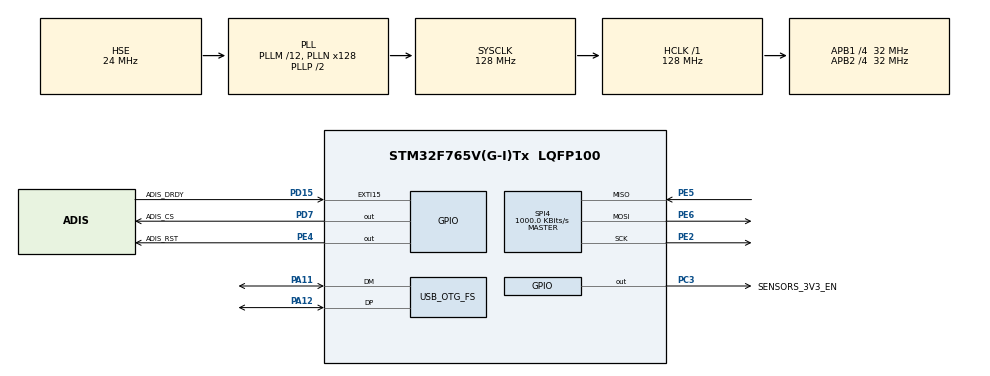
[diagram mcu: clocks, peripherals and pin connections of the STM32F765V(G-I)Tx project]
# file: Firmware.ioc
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Mcu.Family=STM32F7
Mcu.Name=STM32F765V(G-I)Tx
Mcu.Package=LQFP100
NVIC.EXTI15_10_IRQn=true\:0\:0\:false\:false\:true\:true\:true
NVIC.OTG_FS_IRQn=true\:0\:0\:false\:false\:true\:false\:true
NVIC.PriorityGroup=NVIC_PRIORITYGROUP_4
NVIC.TIM1_UP_TIM10_IRQn=true\:0\:0\:false\:false\:true\:true\:true
PA11.Mode=Device_Only
PA11.Signal=USB_OTG_FS_DM
PA12.Mode=Device_Only
PA12.Signal=USB_OTG_FS_DP
PA13.Mode=Serial_Wire
PA13.Signal=SYS_JTMS-SWDIO
PA14.Mode=Serial_Wire
PA14.Signal=SYS_JTCK-SWCLK
PC3.GPIO_Label=SENSORS_3V3_EN
PC3.PinState=GPIO_PIN_SET
PC3.Signal=GPIO_Output
PD15.GPIO_Label=ADIS_DRDY
PD15.Signal=GPXTI15
PD7.GPIO_Label=ADIS_CS
PD7.PinState=GPIO_PIN_SET
PD7.Signal=GPIO_Output
PE2.Mode=Full_Duplex_Master
PE2.Signal=SPI4_SCK
PE4.GPIO_Label=ADIS_RST
PE4.GPIO_ModeDefaultOutputPP=GPIO_MODE_OUTPUT_OD
PE4.GPIO_PuPd=GPIO_PULLUP
PE4.PinState=GPIO_PIN_SET
PE4.Signal=GPIO_Output
PE5.Mode=Full_Duplex_Master
PE5.Signal=SPI4_MISO
PE6.Mode=Full_Duplex_Master
PE6.Signal=SPI4_MOSI
PH0/OSC_IN.Mode=HSE-External-Oscillator
PH0/OSC_IN.Signal=RCC_OSC_IN
PH1/OSC_OUT.Mode=HSE-External-Oscillator
PH1/OSC_OUT.Signal=RCC_OSC_OUT
ProjectManager.HeapSize=0x1000
ProjectManager.StackSize=0x1000
ProjectManager.TargetToolchain=MDK-ARM V5
RCC.AHBFreq_Value=128000000
RCC.APB1CLKDivider=RCC_HCLK_DIV4
RCC.APB1Freq_Value=32000000
RCC.APB1TimFreq_Value=64000000
RCC.APB2CLKDivider=RCC_HCLK_DIV4
RCC.APB2Freq_Value=32000000
RCC.APB2TimFreq_Value=64000000
RCC.CortexFreq_Value=128000000
RCC.HCLKFreq_Value=128000000
RCC.HSE_VALUE=24000000
RCC.HSI_VALUE=16000000
RCC.LSE_VALUE=32768
RCC.PLL48CLockSelection=RCC_CLK48SOURCE_PLLSAIP
RCC.PLLM=12
RCC.PLLN=128
RCC.PLLQ=5
RCC.PLLSAIN=96
RCC.PLLSAIP=RCC_PLLSAIP_DIV4
RCC.SYSCLKFreq_VALUE=128000000
RCC.SYSCLKSource=RCC_SYSCLKSOURCE_PLLCLK
RCC.USBFreq_Value=48000000
RCC.VCOOutputFreq_Value=256000000
SPI4.BaudRatePrescaler=SPI_BAUDRATEPRESCALER_32
SPI4.CLKPhase=SPI_PHASE_2EDGE
SPI4.CLKPolarity=SPI_POLARITY_HIGH
SPI4.CalculateBaudRate=1000.0 KBits/s
SPI4.DataSize=SPI_DATASIZE_16BIT
SPI4.Direction=SPI_DIRECTION_2LINES
SPI4.Mode=SPI_MODE_MASTER
SPI4.VirtualType=VM_MASTER
TIM1.Period=10-1
TIM1.Prescaler=64-1
USB_DEVICE.APP_RX_DATA_SIZE-CDC_FS=32
USB_DEVICE.APP_TX_DATA_SIZE-CDC_FS=32
USB_DEVICE.CLASS_NAME_FS=CDC
USB_DEVICE.MANUFACTURER_STRING-CDC_FS=wangfugui
USB_DEVICE.PID_CDC_FS=2333
USB_DEVICE.PRODUCT_STRING_CDC_FS=adis16448bridge
USB_DEVICE.VID-CDC_FS=2333
USB_DEVICE.VirtualMode-CDC_FS=Cdc
USB_DEVICE.VirtualModeFS=Cdc_FS
USB_OTG_FS.Sof_enable=DISABLE
USB_OTG_FS.VirtualMode=Device_Only
VP_TIM1_VS_ClockSourceINT.Mode=Internal
VP_USB_DEVICE_VS_USB_DEVICE_CDC_FS.Mode=CDC_FS
board=custom

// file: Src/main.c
/* USER CODE BEGIN Header */
/**
  ******************************************************************************
  * @file           : main.c
  * @brief          : Main program body
  ******************************************************************************
  * @attention
  *
  * <h2><center>&copy; Copyright (c) 2020 STMicroelectronics.
  * All rights reserved.</center></h2>
  *
  * This software component is licensed by ST under Ultimate Liberty license
  * SLA0044, the "License"; You may not use this file except in compliance with
  * the License. You may obtain a copy of the License at:
  *                             www.st.com/SLA0044
  *
  ******************************************************************************
  */
/* USER CODE END Header */

#include "main.h"
#include "usb_device.h"

/* USER CODE BEGIN Includes */
//#include "usbd_customhid.h"
//#include "usbd_hid.h"
#include "usbd_cdc_if.h"
/* USER CODE END Includes */

SPI_HandleTypeDef hspi4;

TIM_HandleTypeDef htim1;

/* USER CODE BEGIN PV */
extern USBD_HandleTypeDef hUsbDeviceFS;
/* USER CODE END PV */

void SystemClock_Config(void);
static void MX_GPIO_Init(void);
static void MX_SPI4_Init(void);
static void MX_TIM1_Init(void);

int main(void)
{
  /* USER CODE BEGIN 1 */
//// HID Mouse
//  struct mouseHID_t {
//      uint8_t buttons;
//      int8_t x;
//      int8_t y;
//      int8_t wheel;
//  };
//  struct mouseHID_t mouseHID;
//  mouseHID.buttons = 0;
//  mouseHID.x = 10;
//  mouseHID.y = 0;
//  mouseHID.wheel = 0;
  /* USER CODE END 1 */

  /* MCU Configuration--------------------------------------------------------*/

  /* Reset of all peripherals, Initializes the Flash interface and the Systick. */
  HAL_Init();

  /* Configure the system clock */
  SystemClock_Config();

  /* Initialize all configured peripherals */
  MX_GPIO_Init();
  MX_SPI4_Init();
  MX_USB_DEVICE_Init();
  MX_TIM1_Init();
  /* USER CODE BEGIN 2 */
  unsigned char buf[32];
  /* USER CODE END 2 */

  /* Infinite loop */
  while (1)
  {

    /* USER CODE BEGIN 3 */
    #define ADIS_LEN 14
    int16_t spi_addrs[ADIS_LEN]={0x3e00}, spi_buf[ADIS_LEN];

    HAL_GPIO_WritePin(ADIS_CS_GPIO_Port, ADIS_CS_Pin, 0);
    HAL_SPI_TransmitReceive(&hspi4,(uint8_t*)spi_addrs,(uint8_t*)spi_buf,ADIS_LEN+2,1000);
    HAL_GPIO_WritePin(ADIS_CS_GPIO_Port, ADIS_CS_Pin, 1);

    float gx = spi_buf[2]/25.f;
    float gy = spi_buf[3]/25.f;
    float gz = spi_buf[4]/25.f;

    float ax = spi_buf[5]/1200.f*9.8f;
    float ay = spi_buf[6]/1200.f*9.8f;
    float az = spi_buf[7]/1200.f*9.8f;

    char cdc_buf[200];
    sprintf(cdc_buf,"G: %+7.2f %+7.2f %+7.2f  A: %+6.2f %+6.2f %+6.2f\r\n",gx,gy,gz,ax,ay,az);
    CDC_Transmit_FS((uint8_t*)cdc_buf, strlen(cdc_buf));

    HAL_Delay(100);

  }
  /* USER CODE END 3 */
}

void SystemClock_Config(void)
{
  RCC_OscInitTypeDef RCC_OscInitStruct = {0};
  RCC_ClkInitTypeDef RCC_ClkInitStruct = {0};
  RCC_PeriphCLKInitTypeDef PeriphClkInitStruct = {0};

  /** Configure the main internal regulator output voltage
  */
  __HAL_RCC_PWR_CLK_ENABLE();
  __HAL_PWR_VOLTAGESCALING_CONFIG(PWR_REGULATOR_VOLTAGE_SCALE3);
  /** Initializes the CPU, AHB and APB busses clocks
  */
  RCC_OscInitStruct.OscillatorType = RCC_OSCILLATORTYPE_HSE;
  RCC_OscInitStruct.HSEState = RCC_HSE_ON;
  RCC_OscInitStruct.PLL.PLLState = RCC_PLL_ON;
  RCC_OscInitStruct.PLL.PLLSource = RCC_PLLSOURCE_HSE;
  RCC_OscInitStruct.PLL.PLLM = 12;
  RCC_OscInitStruct.PLL.PLLN = 128;
  RCC_OscInitStruct.PLL.PLLP = RCC_PLLP_DIV2;
  RCC_OscInitStruct.PLL.PLLQ = 5;
  if (HAL_RCC_OscConfig(&RCC_OscInitStruct) != HAL_OK)
  {
    Error_Handler();
  }
  /** Initializes the CPU, AHB and APB busses clocks
  */
  RCC_ClkInitStruct.ClockType = RCC_CLOCKTYPE_HCLK|RCC_CLOCKTYPE_SYSCLK
                              |RCC_CLOCKTYPE_PCLK1|RCC_CLOCKTYPE_PCLK2;
  RCC_ClkInitStruct.SYSCLKSource = RCC_SYSCLKSOURCE_PLLCLK;
  RCC_ClkInitStruct.AHBCLKDivider = RCC_SYSCLK_DIV1;
  RCC_ClkInitStruct.APB1CLKDivider = RCC_HCLK_DIV4;
  RCC_ClkInitStruct.APB2CLKDivider = RCC_HCLK_DIV4;

  if (HAL_RCC_ClockConfig(&RCC_ClkInitStruct, FLASH_LATENCY_4) != HAL_OK)
  {
    Error_Handler();
  }
  PeriphClkInitStruct.PeriphClockSelection = RCC_PERIPHCLK_CLK48;
  PeriphClkInitStruct.PLLSAI.PLLSAIN = 96;
  PeriphClkInitStruct.PLLSAI.PLLSAIR = 2;
  PeriphClkInitStruct.PLLSAI.PLLSAIQ = 2;
  PeriphClkInitStruct.PLLSAI.PLLSAIP = RCC_PLLSAIP_DIV4;
  PeriphClkInitStruct.PLLSAIDivQ = 1;
  PeriphClkInitStruct.PLLSAIDivR = RCC_PLLSAIDIVR_2;
  PeriphClkInitStruct.Clk48ClockSelection = RCC_CLK48SOURCE_PLLSAIP;
  if (HAL_RCCEx_PeriphCLKConfig(&PeriphClkInitStruct) != HAL_OK)
  {
    Error_Handler();
  }
}

static void MX_SPI4_Init(void)
{

  /* SPI4 parameter configuration*/
  hspi4.Instance = SPI4;
  hspi4.Init.Mode = SPI_MODE_MASTER;
  hspi4.Init.Direction = SPI_DIRECTION_2LINES;
  hspi4.Init.DataSize = SPI_DATASIZE_16BIT;
  hspi4.Init.CLKPolarity = SPI_POLARITY_HIGH;
  hspi4.Init.CLKPhase = SPI_PHASE_2EDGE;
  hspi4.Init.NSS = SPI_NSS_SOFT;
  hspi4.Init.BaudRatePrescaler = SPI_BAUDRATEPRESCALER_32;
  hspi4.Init.FirstBit = SPI_FIRSTBIT_MSB;
  hspi4.Init.TIMode = SPI_TIMODE_DISABLE;
  hspi4.Init.CRCCalculation = SPI_CRCCALCULATION_DISABLE;
  hspi4.Init.CRCPolynomial = 7;
  hspi4.Init.CRCLength = SPI_CRC_LENGTH_DATASIZE;
  hspi4.Init.NSSPMode = SPI_NSS_PULSE_DISABLE;
  if (HAL_SPI_Init(&hspi4) != HAL_OK)
  {
    Error_Handler();
  }

}

static void MX_TIM1_Init(void)
{

  TIM_ClockConfigTypeDef sClockSourceConfig = {0};
  TIM_MasterConfigTypeDef sMasterConfig = {0};

  htim1.Instance = TIM1;
  htim1.Init.Prescaler = 64-1;
  htim1.Init.CounterMode = TIM_COUNTERMODE_UP;
  htim1.Init.Period = 10-1;
  htim1.Init.ClockDivision = TIM_CLOCKDIVISION_DIV1;
  htim1.Init.RepetitionCounter = 0;
  htim1.Init.AutoReloadPreload = TIM_AUTORELOAD_PRELOAD_DISABLE;
  if (HAL_TIM_Base_Init(&htim1) != HAL_OK)
  {
    Error_Handler();
  }
  sClockSourceConfig.ClockSource = TIM_CLOCKSOURCE_INTERNAL;
  if (HAL_TIM_ConfigClockSource(&htim1, &sClockSourceConfig) != HAL_OK)
  {
    Error_Handler();
  }
  sMasterConfig.MasterOutputTrigger = TIM_TRGO_RESET;
  sMasterConfig.MasterOutputTrigger2 = TIM_TRGO2_RESET;
  sMasterConfig.MasterSlaveMode = TIM_MASTERSLAVEMODE_DISABLE;
  if (HAL_TIMEx_MasterConfigSynchronization(&htim1, &sMasterConfig) != HAL_OK)
  {
    Error_Handler();
  }

}

static void MX_GPIO_Init(void)
{
  GPIO_InitTypeDef GPIO_InitStruct = {0};

  /* GPIO Ports Clock Enable */
  __HAL_RCC_GPIOE_CLK_ENABLE();
  __HAL_RCC_GPIOH_CLK_ENABLE();
  __HAL_RCC_GPIOC_CLK_ENABLE();
  __HAL_RCC_GPIOD_CLK_ENABLE();
  __HAL_RCC_GPIOA_CLK_ENABLE();

  /*Configure GPIO pin Output Level */
  HAL_GPIO_WritePin(ADIS_RST_GPIO_Port, ADIS_RST_Pin, GPIO_PIN_SET);

  /*Configure GPIO pin Output Level */
  HAL_GPIO_WritePin(SENSORS_3V3_EN_GPIO_Port, SENSORS_3V3_EN_Pin, GPIO_PIN_SET);

  /*Configure GPIO pin Output Level */
  HAL_GPIO_WritePin(ADIS_CS_GPIO_Port, ADIS_CS_Pin, GPIO_PIN_SET);

  /*Configure GPIO pin : ADIS_RST_Pin */
  GPIO_InitStruct.Pin = ADIS_RST_Pin;
  GPIO_InitStruct.Mode = GPIO_MODE_OUTPUT_OD;
  GPIO_InitStruct.Pull = GPIO_PULLUP;
  GPIO_InitStruct.Speed = GPIO_SPEED_FREQ_LOW;
  HAL_GPIO_Init(ADIS_RST_GPIO_Port, &GPIO_InitStruct);

  /*Configure GPIO pin : SENSORS_3V3_EN_Pin */
  GPIO_InitStruct.Pin = SENSORS_3V3_EN_Pin;
  GPIO_InitStruct.Mode = GPIO_MODE_OUTPUT_PP;
  GPIO_InitStruct.Pull = GPIO_NOPULL;
  GPIO_InitStruct.Speed = GPIO_SPEED_FREQ_LOW;
  HAL_GPIO_Init(SENSORS_3V3_EN_GPIO_Port, &GPIO_InitStruct);

  /*Configure GPIO pin : ADIS_DRDY_Pin */
  GPIO_InitStruct.Pin = ADIS_DRDY_Pin;
  GPIO_InitStruct.Mode = GPIO_MODE_IT_RISING;
  GPIO_InitStruct.Pull = GPIO_NOPULL;
  HAL_GPIO_Init(ADIS_DRDY_GPIO_Port, &GPIO_InitStruct);

  /*Configure GPIO pins : PC11 PC12 */
  GPIO_InitStruct.Pin = GPIO_PIN_11|GPIO_PIN_12;
  GPIO_InitStruct.Mode = GPIO_MODE_AF_PP;
  GPIO_InitStruct.Pull = GPIO_NOPULL;
  GPIO_InitStruct.Speed = GPIO_SPEED_FREQ_VERY_HIGH;
  GPIO_InitStruct.Alternate = GPIO_AF12_SDMMC1;
  HAL_GPIO_Init(GPIOC, &GPIO_InitStruct);

  /*Configure GPIO pin : ADIS_CS_Pin */
  GPIO_InitStruct.Pin = ADIS_CS_Pin;
  GPIO_InitStruct.Mode = GPIO_MODE_OUTPUT_PP;
  GPIO_InitStruct.Pull = GPIO_NOPULL;
  GPIO_InitStruct.Speed = GPIO_SPEED_FREQ_LOW;
  HAL_GPIO_Init(ADIS_CS_GPIO_Port, &GPIO_InitStruct);

  /* EXTI interrupt init*/
  HAL_NVIC_SetPriority(EXTI15_10_IRQn, 0, 0);
  HAL_NVIC_EnableIRQ(EXTI15_10_IRQn);

}

void Error_Handler(void)
{
}

/************************ (C) COPYRIGHT STMicroelectronics *****END OF FILE****/
